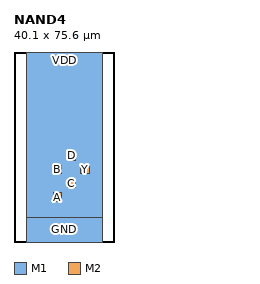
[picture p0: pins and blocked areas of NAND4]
MACRO NAND4
  CLASS CORE ;
  ORIGIN 0 0 ;
  SIZE 40.100 BY 75.600 ;
  SYMMETRY X Y ;
  SITE TR1um_access_site ;
  PIN VDD
    DIRECTION INOUT ;
    USE POWER ;
    PORT
      LAYER M1 ;
        RECT 5.000 0.000 35.100 75.600 ;
    END
  END VDD
  PIN GND
    DIRECTION INOUT ;
    USE GROUND ;
    PORT
      LAYER M1 ;
        RECT 5.000 0.000 35.100 9.800 ;
    END
  END GND
  PIN A
    DIRECTION INPUT ;
    USE SIGNAL ;
    PORT
      LAYER M2 ;
        RECT 15.600 16.100 19.000 19.500 ;
    END
  END A
  PIN B
    DIRECTION INPUT ;
    USE SIGNAL ;
    PORT
      LAYER M2 ;
        RECT 15.600 27.100 19.000 30.500 ;
    END
  END B
  PIN C
    DIRECTION INPUT ;
    USE SIGNAL ;
    PORT
      LAYER M2 ;
        RECT 21.100 21.600 24.500 25.000 ;
    END
  END C
  PIN D
    DIRECTION INPUT ;
    USE SIGNAL ;
    PORT
      LAYER M2 ;
        RECT 21.100 32.600 24.500 36.000 ;
    END
  END D
  PIN Y
    DIRECTION OUTPUT ;
    USE SIGNAL ;
    PORT
      LAYER M2 ;
        RECT 26.600 27.100 30.000 30.500 ;
    END
  END Y
  OBS
    LAYER M1 ;
      RECT 13.100 6.400 15.700 9.800 ;
    LAYER M1 ;
      RECT 17.100 6.400 19.150 9.800 ;
    LAYER M1 ;
      RECT 21.100 6.400 23.700 9.800 ;
    LAYER M1 ;
      RECT 7.200 11.700 19.000 19.500 ;
    LAYER M1 ;
      RECT 17.900 22.400 19.150 25.000 ;
    LAYER M1 ;
      RECT 20.950 21.600 24.500 25.000 ;
    LAYER M1 ;
      RECT 10.500 23.900 19.000 30.500 ;
    LAYER M1 ;
      RECT 21.100 28.400 24.800 36.000 ;
    LAYER M1 ;
      RECT 13.100 37.500 19.150 51.200 ;
    LAYER M1 ;
      RECT 20.950 6.400 30.000 51.200 ;
    LAYER V1 ;
      RECT 16.600 17.100 18.000 18.500 ;
    LAYER V1 ;
      RECT 22.100 22.600 23.500 24.000 ;
    LAYER V1 ;
      RECT 16.600 28.100 18.000 29.500 ;
    LAYER V1 ;
      RECT 27.600 28.100 29.000 29.500 ;
    LAYER V1 ;
      RECT 22.100 33.600 23.500 35.000 ;
  END
END NAND4
